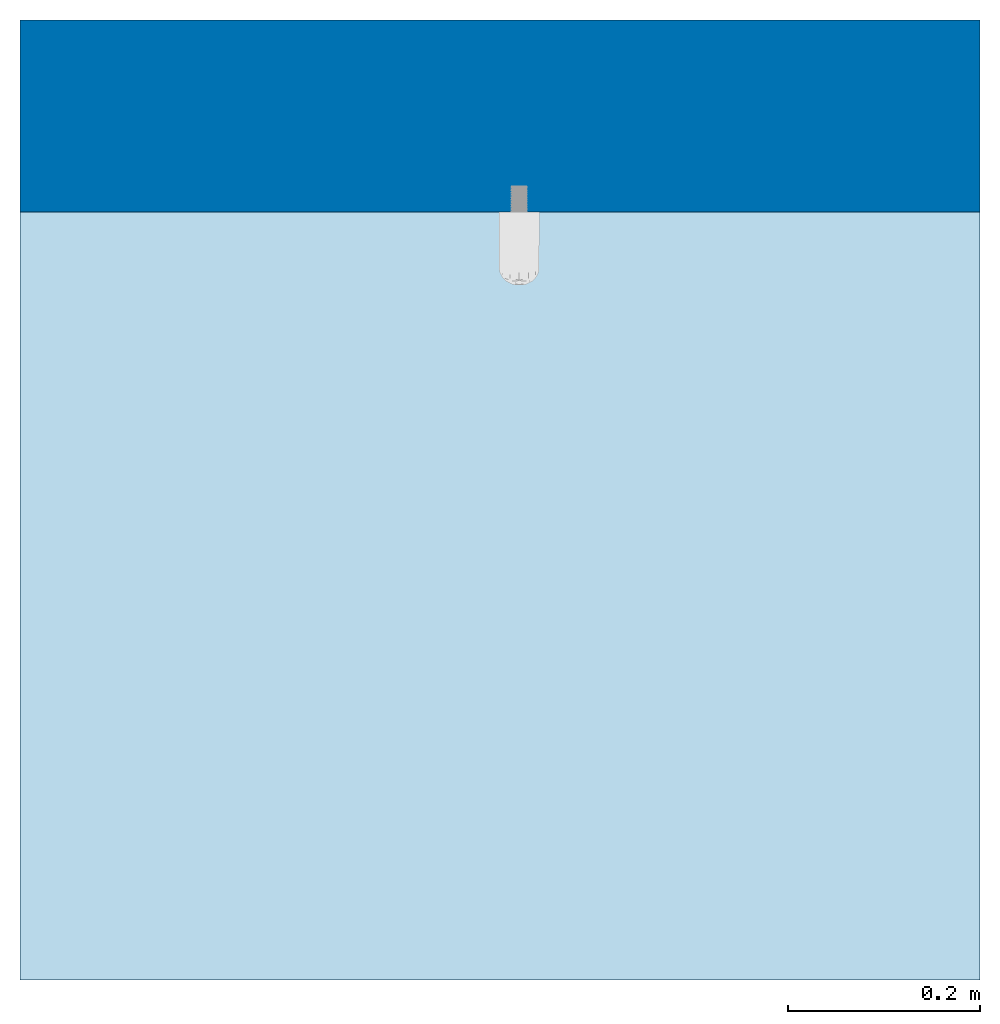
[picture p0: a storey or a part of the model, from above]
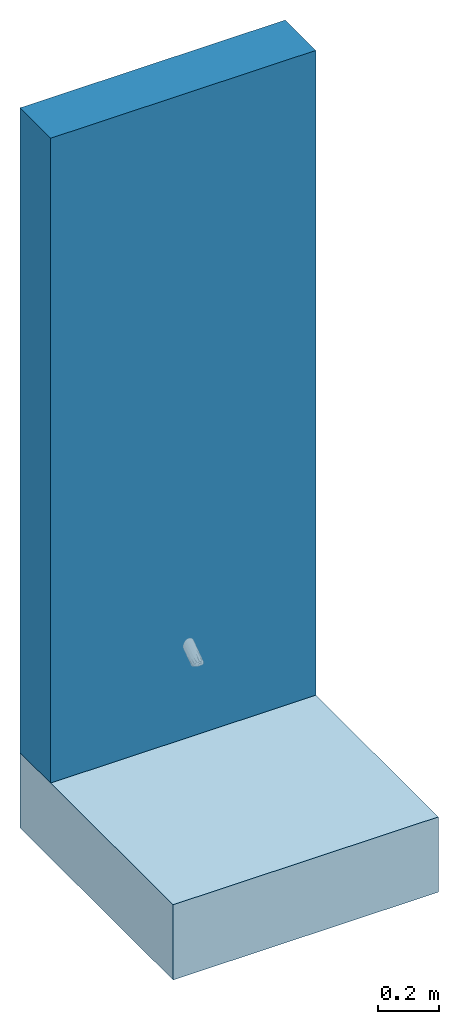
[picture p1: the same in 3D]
Properties of the parts of a building model (IFC2X3)

# File
Description: ViewDefinition [CoordinationView_V2.0]
Time: 2017-06-29T15:06:51
Written by: The EXPRESS Data Manager Version 5.02.0100.07 : 28 Aug 2013
Made in: 20140606_1530(x64) - Exporter 15.7.0.0 - Alternate UI 15.7.0.0
Comment: STEP Physical File produced by: The EXPRESS Data Manager Version 5.02.0100.07 : 28 Aug 2013 * Module: EDMstepFileFactory/EDMstandAlone * Creation date: Thu Jun 29 15:06:51 2017 * Host: Polantis_Siza * Database: C:\Users\POLANT~1\AppData\Local\Temp\{03B1F996-FA2F-41B8-BBFB-AB0893029D78}\ifc * Database version: 5507 * Database creation date: Thu Jun 29 15:06:50 2017 * Schema: IFC2X3 * Model: DataRepository.ifc * Model creation date: Thu Jun 29 15:06:51 2017 * Header model: DataRepository.ifc_HeaderModel * Header model creation date: Thu Jun 29 15:06:51 2017 * EDMuser: sdai-user * EDMgroup: sdai-group * License ID and type: 5605 : Permanent license. Expiry date: * EDMstepFileFactory options: 020000

# IfcProject
LongName: C:\Users\Polantis_Production\Desktop\DLB090002-FR.ifc

# IfcSite, Default
RefLatitude: 42, 24, 53, 508911; RefLongitude: -71, -15, -29, -58837; RefElevation: 0 mm
Other - Category: Project Information

# IfcBuilding
Pset_BuildingCommon - NumberOfStoreys: 1
Other - Category: Project Information

# IfcBuildingStorey, Level 1
LongName: Level 1; Elevation: 0 mm
Other(Type) - Category: Levels; Family Name: Level
Constraints - Elevation: 0 mm
Dimensions - Computation Height: 0 mm
Identity Data - Structural: no; Building Story: yes; Name: Level 1
Other - Category: Levels; Family: Level: Level 1; Family and Type: Level: Level 1; Type: Level: Level 1; Type Id: Level: Level 1
Constraints(Type) - Elevation Base: Project Base Point
Graphics(Type) - Color: 0; Line Pattern: Solid; Line Weight: 1; Symbol at End 1 Default: no; Symbol at End 2 Default: yes
Identity Data(Type) - Type Name: Level 1

# IfcFlowTerminal: Type 1, DLB090002-FR:Type 1:10156
In: Level 1
Material: Brass, Chrome plated
Pset_ManufacturerTypeInformation - Manufacturer: DELABIE
Pset_DistributionFlowElementCommon - Reference: Type 1
Constraints - Elevation: 318.113 mm; Level: Level: Level 1
Dimensions - Area: 0.0109907 m2; Volume: 0.000105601 m3
Identity Data - Mark: 1
Mechanical - System Classification: Domestic Cold Water
Other - Category: Plumbing Fixtures; Family: DLB090002-FR: Type 1; Family and Type: DLB090002-FR: Type 1; Host Id: Basic Wall: Wall 1; Type: DLB090002-FR: Type 1; Type Id: DLB090002-FR: Type 1
Phasing - Phase Created: New Construction
Data(Type) - Nom: 712000
Dimensions(Type) - Profondeur: 75 mm; Raccordement: M1/2"
Identity Data(Type) - Débit eau: 6 l/min à 3 bar; Descriptif: Pomme de douche fixe antitartre encastrée : Débit 6 l/min à 3 bar. Régulation automatique du débit. Diffuseur antitartre et antiligature à jet orientable et verrouillable. Laiton massif chromé. Fixation avec vis de blocage invisible. Vidage systématique après utilisation (pas de rétention d'eau ni d'impuretés). Arrivée M1/2".; Description: DELABIE, fabricant français, est le leader européen de l'équipement sanitaire pour les établissements recevant du public. Robinetteries, solutions pour personnes à mobilité réduite, appareils sanitaires, destinés aux écoles, lieux de loisirs, bureaux, hôpitaux, aéroports, ...; Fabricant: DELABIE; Famille de produits: Douche; Lien CCTP: http://www.delabie.fr/produits/712000; Lien certification: http://www.delabie.fr/produits/712000; Lien fiche produit: http://www.delabie.fr/produits/712000; Lien notice d'installation: http://www.delabie.fr/produits/712000; Manufacturer: DELABIE; Model: TONIC JET; OmniClass Number: 23.45.55.17; OmniClass Title: Mixing Faucets; Polantis code: DLB090002; Type Comments: Pomme de douche antitartre; Type Name: Type 1; URL: http://www.delabie.fr
Materials and Finishes(Type) - DLB090002: Brass, Chrome plated; Finition: Laiton massif chromé
Other(Type) - Category: Plumbing Fixtures; Family Name: DLB090002-FR

# IfcSlab: Floor:Floor 1, Floor:Floor 1:2454
In: Level 1
PredefinedType: FLOOR; Material: <Unnamed> 300 mm
Pset_SlabCommon - LoadBearing: no; Reference: Floor 1; IsExternal: no; PitchAngle: 0 deg
Constraints - Related to Mass: no; Room Bounding: yes; Height Offset From Level: 0 mm; Level: Level: Level 1
Dimensions - Area: 1 m2; Perimeter: 4000 mm; Thickness: 300 mm; Volume: 0.3 m3
Other - Category: Floors; Family: Floor: Floor 1; Family and Type: Floor: Floor 1; Type: Floor: Floor 1; Type Id: Floor: Floor 1
Phasing - Phase Created: New Construction
Structural - Enable Analytical Model: no; Structural: no
Analytical Properties(Type) - Roughness: 1; Absorptance: 0.1
Construction(Type) - Default Thickness: 300 mm
Graphics(Type) - Coarse Scale Fill Color: 0
Identity Data(Type) - Type Name: Floor 1
Other(Type) - Category: Floors; Family Name: Floor

# IfcWallStandardCase: Basic Wall:Wall 1, Basic Wall:Wall 1:2416
In: Level 1
Type - PredefinedType: STANDARD; Material: Default Wall 200 mm
Type - Analytical Properties(Type) - Absorptance: 0.1; Roughness: 1
Type - Construction(Type) - Function: Exterior; Width: 200 mm; Wrapping at Inserts: Do not wrap
Type - Graphics(Type) - Coarse Scale Fill Color: 0
Type - Identity Data(Type) - Type Name: Wall 1
Type - Other(Type) - Category: Walls; Family Name: Basic Wall
Constraints - Base Constraint: Level: Level 1; Base Extension Distance: 0 mm; Base is Attached: no; Base Offset: 0 mm; Location Line: Wall Centerline; Related to Mass: no; Room Bounding: yes; Top Extension Distance: 0 mm; Top is Attached: no; Top Offset: 0 mm; Unconnected Height: 2570.35 mm
Dimensions - Area: 2.57035 m2; Length: 1000 mm; Volume: 0.51407 m3
Other - Category: Walls; Family: Basic Wall: Wall 1; Family and Type: Basic Wall: Wall 1; Type: Basic Wall: Wall 1; Type Id: Basic Wall: Wall 1
Phasing - Phase Created: New Construction
Structural - Enable Analytical Model: no; Structural: no; Structural Usage: Non-bearing
Pset_WallCommon - Reference: Wall 1; LoadBearing: no; ExtendToStructure: no; IsExternal: yes
